One B-rep face of a CAD part: STEP entity #261.
In plain terms, the planar face has unit normal (0, 0, 1).
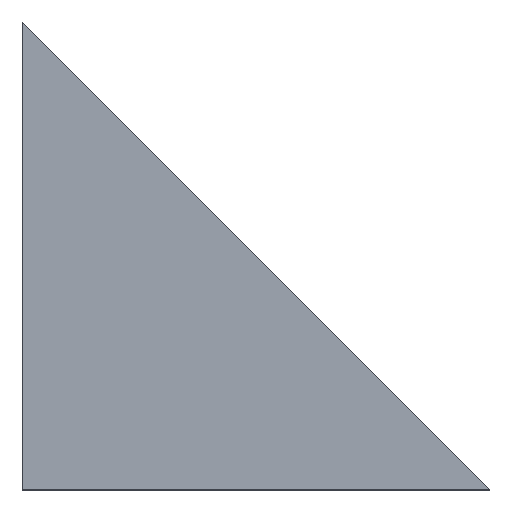
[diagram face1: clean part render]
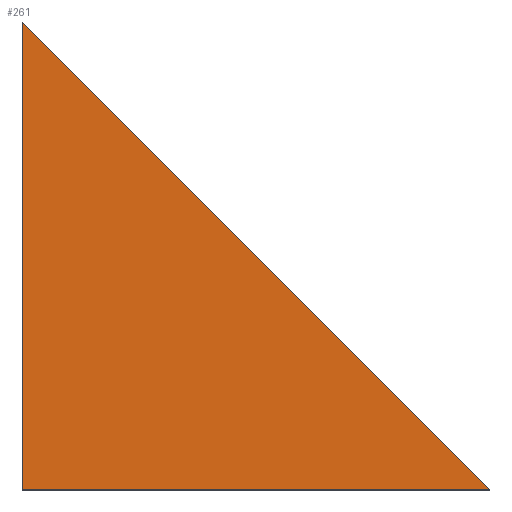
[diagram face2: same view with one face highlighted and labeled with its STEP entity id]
Its self-contained STEP definition (entity closure, numbers rounded to 3 decimals):
#24 = VERTEX_POINT('',#25);
#25 = CARTESIAN_POINT('',(0.,0.,12.));
#32 = PLANE('',#33);
#33 = AXIS2_PLACEMENT_3D('',#34,#35,#36);
#34 = CARTESIAN_POINT('',(0.,0.,0.));
#35 = DIRECTION('',(0.,1.,0.));
#36 = DIRECTION('',(1.,0.,0.));
#44 = PLANE('',#45);
#45 = AXIS2_PLACEMENT_3D('',#46,#47,#48);
#46 = CARTESIAN_POINT('',(0.,150.,0.));
#47 = DIRECTION('',(1.,0.,-0.));
#48 = DIRECTION('',(0.,-1.,0.));
#56 = EDGE_CURVE('',#24,#57,#59,.T.);
#57 = VERTEX_POINT('',#58);
#58 = CARTESIAN_POINT('',(150.,0.,12.));
#59 = SURFACE_CURVE('',#60,(#64,#71),.PCURVE_S1.);
#60 = LINE('',#61,#62);
#61 = CARTESIAN_POINT('',(0.,0.,12.));
#62 = VECTOR('',#63,1.);
#63 = DIRECTION('',(1.,0.,0.));
#64 = PCURVE('',#32,#65);
#65 = DEFINITIONAL_REPRESENTATION('',(#66),#70);
#66 = LINE('',#67,#68);
#67 = CARTESIAN_POINT('',(0.,-12.));
#68 = VECTOR('',#69,1.);
#69 = DIRECTION('',(1.,0.));
#70 = ( GEOMETRIC_REPRESENTATION_CONTEXT(2) 
PARAMETRIC_REPRESENTATION_CONTEXT() REPRESENTATION_CONTEXT('2D SPACE',''
  ) );
#71 = PCURVE('',#72,#77);
#72 = PLANE('',#73);
#73 = AXIS2_PLACEMENT_3D('',#74,#75,#76);
#74 = CARTESIAN_POINT('',(53.033,53.033,12.));
#75 = DIRECTION('',(0.,0.,1.));
#76 = DIRECTION('',(1.,0.,-0.));
#77 = DEFINITIONAL_REPRESENTATION('',(#78),#82);
#78 = LINE('',#79,#80);
#79 = CARTESIAN_POINT('',(-53.033,-53.033));
#80 = VECTOR('',#81,1.);
#81 = DIRECTION('',(1.,0.));
#82 = ( GEOMETRIC_REPRESENTATION_CONTEXT(2) 
PARAMETRIC_REPRESENTATION_CONTEXT() REPRESENTATION_CONTEXT('2D SPACE',''
  ) );
#100 = PLANE('',#101);
#101 = AXIS2_PLACEMENT_3D('',#102,#103,#104);
#102 = CARTESIAN_POINT('',(150.,0.,0.));
#103 = DIRECTION('',(-0.707,-0.707,0.));
#104 = DIRECTION('',(-0.707,0.707,0.));
#142 = EDGE_CURVE('',#57,#143,#145,.T.);
#143 = VERTEX_POINT('',#144);
#144 = CARTESIAN_POINT('',(0.,150.,12.));
#145 = SURFACE_CURVE('',#146,(#150,#157),.PCURVE_S1.);
#146 = LINE('',#147,#148);
#147 = CARTESIAN_POINT('',(150.,0.,12.));
#148 = VECTOR('',#149,1.);
#149 = DIRECTION('',(-0.707,0.707,0.));
#150 = PCURVE('',#100,#151);
#151 = DEFINITIONAL_REPRESENTATION('',(#152),#156);
#152 = LINE('',#153,#154);
#153 = CARTESIAN_POINT('',(0.,-12.));
#154 = VECTOR('',#155,1.);
#155 = DIRECTION('',(1.,0.));
#156 = ( GEOMETRIC_REPRESENTATION_CONTEXT(2) 
PARAMETRIC_REPRESENTATION_CONTEXT() REPRESENTATION_CONTEXT('2D SPACE',''
  ) );
#157 = PCURVE('',#72,#158);
#158 = DEFINITIONAL_REPRESENTATION('',(#159),#163);
#159 = LINE('',#160,#161);
#160 = CARTESIAN_POINT('',(96.967,-53.033));
#161 = VECTOR('',#162,1.);
#162 = DIRECTION('',(-0.707,0.707));
#163 = ( GEOMETRIC_REPRESENTATION_CONTEXT(2) 
PARAMETRIC_REPRESENTATION_CONTEXT() REPRESENTATION_CONTEXT('2D SPACE',''
  ) );
#213 = EDGE_CURVE('',#143,#24,#214,.T.);
#214 = SURFACE_CURVE('',#215,(#219,#226),.PCURVE_S1.);
#215 = LINE('',#216,#217);
#216 = CARTESIAN_POINT('',(0.,150.,12.));
#217 = VECTOR('',#218,1.);
#218 = DIRECTION('',(0.,-1.,0.));
#219 = PCURVE('',#44,#220);
#220 = DEFINITIONAL_REPRESENTATION('',(#221),#225);
#221 = LINE('',#222,#223);
#222 = CARTESIAN_POINT('',(0.,-12.));
#223 = VECTOR('',#224,1.);
#224 = DIRECTION('',(1.,0.));
#225 = ( GEOMETRIC_REPRESENTATION_CONTEXT(2) 
PARAMETRIC_REPRESENTATION_CONTEXT() REPRESENTATION_CONTEXT('2D SPACE',''
  ) );
#226 = PCURVE('',#72,#227);
#227 = DEFINITIONAL_REPRESENTATION('',(#228),#232);
#228 = LINE('',#229,#230);
#229 = CARTESIAN_POINT('',(-53.033,96.967));
#230 = VECTOR('',#231,1.);
#231 = DIRECTION('',(0.,-1.));
#232 = ( GEOMETRIC_REPRESENTATION_CONTEXT(2) 
PARAMETRIC_REPRESENTATION_CONTEXT() REPRESENTATION_CONTEXT('2D SPACE',''
  ) );
#261 = ADVANCED_FACE('',(#262),#72,.T.);
#262 = FACE_BOUND('',#263,.T.);
#263 = EDGE_LOOP('',(#264,#265,#266));
#264 = ORIENTED_EDGE('',*,*,#56,.T.);
#265 = ORIENTED_EDGE('',*,*,#142,.T.);
#266 = ORIENTED_EDGE('',*,*,#213,.T.);
